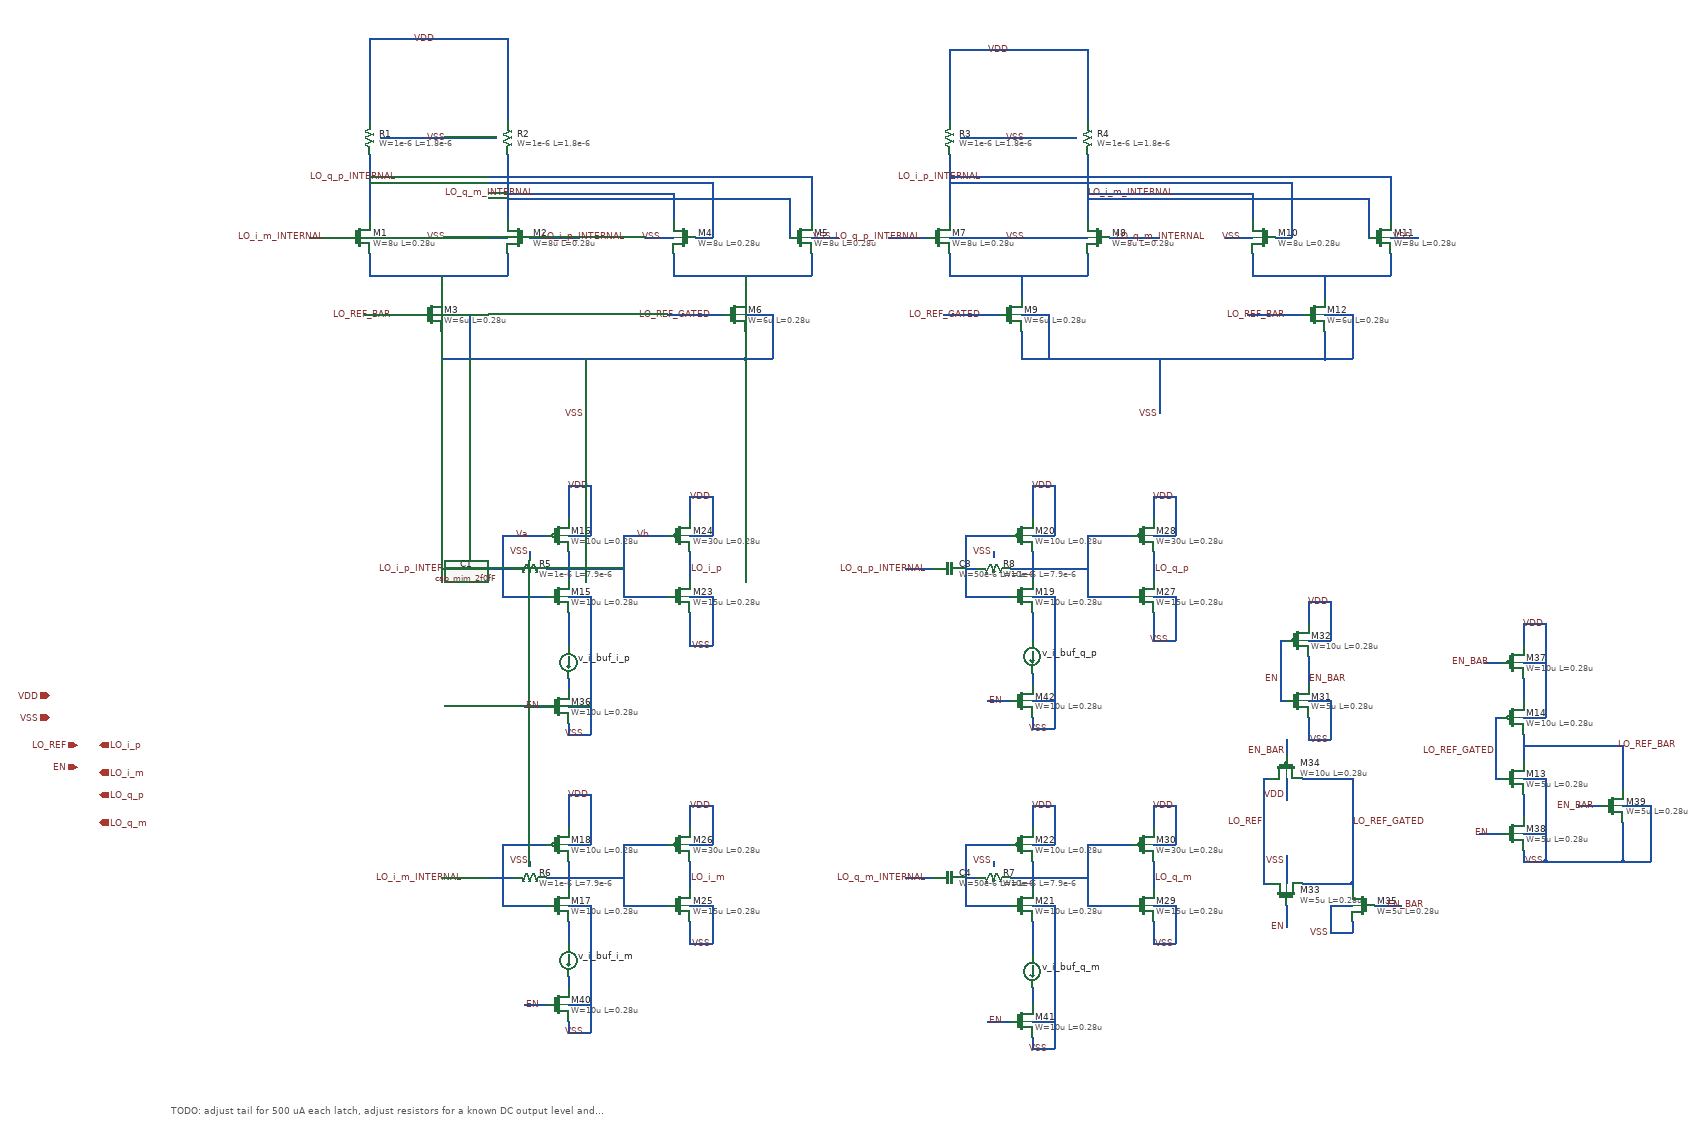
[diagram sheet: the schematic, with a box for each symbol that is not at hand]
v {xschem version=3.4.8RC file_version=1.3}
G {}
K {}
V {}
S {}
F {}
E {}
T {TODO: adjust tail for 500 uA each latch, adjust resistors for a known DC output level and swing, add latch output stage to couple into output buffer. Remove self biasing or add wideband buffer to help with low frequency clock signasl} 50 170 0 0 0.2 0.2 {}
N 410 -1370 410 -1330 {lab=#net1}
N 410 -1330 660 -1330 {lab=#net1}
N 660 -1370 660 -1330 {lab=#net1}
N 540 -1330 540 -1290 {lab=#net1}
N 400 -1260 500 -1260 {lab=LO_REF_BAR}
N 540 -1230 540 -1180 {lab=VSS}
N 300 -1400 370 -1400 {lab=LO_i_m_INTERNAL}
N 700 -1400 790 -1400 {lab=LO_i_p_INTERNAL}
N 660 -1540 660 -1430 {lab=LO_q_m_INTERNAL}
N 410 -1550 410 -1430 {lab=LO_q_p_INTERNAL}
N 410 -1760 660 -1760 {lab=VDD}
N 960 -1370 960 -1330 {lab=#net2}
N 960 -1330 1210 -1330 {lab=#net2}
N 1210 -1370 1210 -1330 {lab=#net2}
N 1090 -1330 1090 -1290 {lab=#net2}
N 950 -1260 1050 -1260 {lab=LO_REF_GATED}
N 1090 -1230 1090 -1180 {lab=VSS}
N 960 -1480 960 -1430 {lab=LO_q_m_INTERNAL}
N 1000 -1400 1030 -1400 {lab=LO_q_p_INTERNAL}
N 1030 -1450 1030 -1400 {lab=LO_q_p_INTERNAL}
N 660 -1480 960 -1480 {lab=LO_q_m_INTERNAL}
N 1030 -1500 1030 -1450 {lab=LO_q_p_INTERNAL}
N 410 -1500 1030 -1500 {lab=LO_q_p_INTERNAL}
N 1170 -1470 1170 -1400 {lab=LO_q_m_INTERNAL}
N 660 -1470 1170 -1470 {lab=LO_q_m_INTERNAL}
N 1210 -1510 1210 -1430 {lab=LO_q_p_INTERNAL}
N 410 -1510 1210 -1510 {lab=LO_q_p_INTERNAL}
N 540 -1180 1090 -1180 {lab=VSS}
N 540 -1260 590 -1260 {lab=VSS}
N 590 -1250 590 -1180 {lab=VSS}
N 590 -1260 590 -1250 {lab=VSS}
N 1090 -1260 1140 -1260 {lab=VSS}
N 1140 -1260 1140 -1180 {lab=VSS}
N 1090 -1180 1140 -1180 {lab=VSS}
N 910 -1400 960 -1400 {lab=VSS}
N 1210 -1400 1260 -1400 {lab=VSS}
N 410 -1400 660 -1400 {lab=VSS}
N 1460 -1370 1460 -1330 {lab=#net3}
N 1460 -1330 1710 -1330 {lab=#net3}
N 1710 -1370 1710 -1330 {lab=#net3}
N 1590 -1330 1590 -1290 {lab=#net3}
N 1450 -1260 1550 -1260 {lab=LO_REF_GATED}
N 1590 -1230 1590 -1180 {lab=VSS}
N 1350 -1400 1420 -1400 {lab=LO_q_p_INTERNAL}
N 1750 -1400 1840 -1400 {lab=LO_q_m_INTERNAL}
N 1710 -1540 1710 -1430 {lab=LO_i_m_INTERNAL}
N 1460 -1550 1460 -1430 {lab=LO_i_p_INTERNAL}
N 1460 -1740 1710 -1740 {lab=VDD}
N 2010 -1370 2010 -1330 {lab=#net4}
N 2010 -1330 2260 -1330 {lab=#net4}
N 2260 -1370 2260 -1330 {lab=#net4}
N 2140 -1330 2140 -1290 {lab=#net4}
N 2000 -1260 2100 -1260 {lab=LO_REF_BAR}
N 2140 -1230 2140 -1180 {lab=VSS}
N 2010 -1480 2010 -1430 {lab=LO_i_m_INTERNAL}
N 2050 -1400 2080 -1400 {lab=LO_i_p_INTERNAL}
N 2080 -1450 2080 -1400 {lab=LO_i_p_INTERNAL}
N 1710 -1480 2010 -1480 {lab=LO_i_m_INTERNAL}
N 2080 -1500 2080 -1450 {lab=LO_i_p_INTERNAL}
N 1460 -1500 2080 -1500 {lab=LO_i_p_INTERNAL}
N 2220 -1470 2220 -1400 {lab=LO_i_m_INTERNAL}
N 1710 -1470 2220 -1470 {lab=LO_i_m_INTERNAL}
N 2260 -1510 2260 -1430 {lab=LO_i_p_INTERNAL}
N 1460 -1510 2260 -1510 {lab=LO_i_p_INTERNAL}
N 1590 -1180 2140 -1180 {lab=VSS}
N 1590 -1260 1640 -1260 {lab=VSS}
N 1640 -1250 1640 -1180 {lab=VSS}
N 1640 -1260 1640 -1250 {lab=VSS}
N 2140 -1260 2190 -1260 {lab=VSS}
N 2190 -1260 2190 -1180 {lab=VSS}
N 2140 -1180 2190 -1180 {lab=VSS}
N 1960 -1400 2010 -1400 {lab=VSS}
N 2260 -1400 2310 -1400 {lab=VSS}
N 1460 -1400 1710 -1400 {lab=VSS}
N 1840 -1120 1840 -1080 {lab=VSS}
N 800 -1120 800 -1080 {lab=VSS}
N 2450 -420 2460 -420 {lab=LO_REF_GATED}
N 2450 -530 2450 -420 {lab=LO_REF_GATED}
N 2450 -530 2460 -530 {lab=LO_REF_GATED}
N 2500 -500 2500 -450 {lab=LO_REF_BAR}
N 2500 -390 2500 -350 {lab=#net5}
N 2500 -530 2540 -530 {lab=VDD}
N 2540 -700 2540 -530 {lab=VDD}
N 2500 -700 2540 -700 {lab=VDD}
N 2500 -420 2540 -420 {lab=VSS}
N 2540 -420 2540 -350 {lab=VSS}
N 2500 -270 2540 -270 {lab=VSS}
N 800 -1170 800 -1120 {lab=VSS}
N 800 -1180 800 -1170 {lab=VSS}
N 1840 -1180 1840 -1120 {lab=VSS}
N 410 -1700 410 -1650 {lab=VDD}
N 660 -1700 660 -1650 {lab=VDD}
N 720 -750 730 -750 {lab=LO_i_p_INTERNAL}
N 650 -860 650 -750 {lab=LO_i_p_INTERNAL}
N 720 -860 730 -860 {lab=LO_i_p_INTERNAL}
N 770 -830 770 -780 {lab=Vb}
N 770 -720 770 -680 {lab=#net6}
N 770 -930 770 -890 {lab=VDD}
N 770 -860 810 -860 {lab=VDD}
N 770 -950 810 -950 {lab=VDD}
N 770 -750 810 -750 {lab=VSS}
N 810 -750 810 -680 {lab=VSS}
N 650 -750 720 -750 {lab=LO_i_p_INTERNAL}
N 650 -860 710 -860 {lab=LO_i_p_INTERNAL}
N 710 -860 720 -860 {lab=LO_i_p_INTERNAL}
N 730 -800 770 -800 {lab=Vb}
N 650 -800 670 -800 {lab=LO_i_p_INTERNAL}
N 540 -800 590 -800 {lab=LO_i_p_INTERNAL}
N 720 -190 730 -190 {lab=LO_i_m_INTERNAL}
N 650 -300 650 -190 {lab=LO_i_m_INTERNAL}
N 720 -300 730 -300 {lab=LO_i_m_INTERNAL}
N 770 -270 770 -220 {lab=#net7}
N 770 -370 770 -330 {lab=VDD}
N 770 -300 810 -300 {lab=VDD}
N 770 -190 810 -190 {lab=VSS}
N 650 -190 720 -190 {lab=LO_i_m_INTERNAL}
N 650 -300 710 -300 {lab=LO_i_m_INTERNAL}
N 710 -300 720 -300 {lab=LO_i_m_INTERNAL}
N 730 -240 770 -240 {lab=#net7}
N 650 -240 670 -240 {lab=LO_i_m_INTERNAL}
N 540 -240 590 -240 {lab=LO_i_m_INTERNAL}
N 1560 -750 1570 -750 {lab=#net8}
N 1490 -860 1490 -750 {lab=#net8}
N 1560 -860 1570 -860 {lab=#net8}
N 1610 -830 1610 -780 {lab=#net9}
N 1610 -720 1610 -680 {lab=#net10}
N 1610 -930 1610 -890 {lab=VDD}
N 1610 -860 1650 -860 {lab=VDD}
N 1610 -750 1650 -750 {lab=VSS}
N 1490 -750 1560 -750 {lab=#net8}
N 1490 -860 1550 -860 {lab=#net8}
N 1550 -860 1560 -860 {lab=#net8}
N 1570 -800 1610 -800 {lab=#net9}
N 1490 -800 1510 -800 {lab=#net8}
N 1380 -800 1430 -800 {lab=LO_q_p_INTERNAL}
N 1560 -190 1570 -190 {lab=#net11}
N 1490 -300 1490 -190 {lab=#net11}
N 1560 -300 1570 -300 {lab=#net11}
N 1610 -270 1610 -220 {lab=#net12}
N 1610 -370 1610 -330 {lab=VDD}
N 1610 -300 1650 -300 {lab=VDD}
N 1610 -190 1650 -190 {lab=VSS}
N 1490 -190 1560 -190 {lab=#net11}
N 1490 -300 1550 -300 {lab=#net11}
N 1550 -300 1560 -300 {lab=#net11}
N 1570 -240 1610 -240 {lab=#net12}
N 1490 -240 1510 -240 {lab=#net11}
N 1380 -240 1430 -240 {lab=LO_q_m_INTERNAL}
N 940 -750 950 -750 {lab=Vb}
N 940 -860 950 -860 {lab=Vb}
N 990 -830 990 -780 {lab=LO_i_p}
N 990 -720 990 -680 {lab=VSS}
N 990 -930 990 -890 {lab=VDD}
N 990 -860 1030 -860 {lab=VDD}
N 1030 -930 1030 -860 {lab=VDD}
N 990 -930 1030 -930 {lab=VDD}
N 990 -750 1030 -750 {lab=VSS}
N 870 -750 940 -750 {lab=Vb}
N 870 -860 930 -860 {lab=Vb}
N 930 -860 940 -860 {lab=Vb}
N 870 -860 870 -750 {lab=Vb}
N 770 -800 870 -800 {lab=Vb}
N 940 -190 950 -190 {lab=#net7}
N 940 -300 950 -300 {lab=#net7}
N 990 -270 990 -220 {lab=LO_i_m}
N 990 -370 990 -330 {lab=VDD}
N 990 -300 1030 -300 {lab=VDD}
N 1030 -370 1030 -300 {lab=VDD}
N 990 -370 1030 -370 {lab=VDD}
N 990 -190 1030 -190 {lab=VSS}
N 870 -190 940 -190 {lab=#net7}
N 870 -300 930 -300 {lab=#net7}
N 930 -300 940 -300 {lab=#net7}
N 870 -300 870 -190 {lab=#net7}
N 770 -240 870 -240 {lab=#net7}
N 1780 -750 1790 -750 {lab=#net9}
N 1780 -860 1790 -860 {lab=#net9}
N 1830 -830 1830 -780 {lab=LO_q_p}
N 1830 -720 1830 -680 {lab=VSS}
N 1830 -930 1830 -890 {lab=VDD}
N 1830 -860 1870 -860 {lab=VDD}
N 1870 -930 1870 -860 {lab=VDD}
N 1830 -930 1870 -930 {lab=VDD}
N 1830 -750 1870 -750 {lab=VSS}
N 1710 -750 1780 -750 {lab=#net9}
N 1710 -860 1770 -860 {lab=#net9}
N 1770 -860 1780 -860 {lab=#net9}
N 1710 -860 1710 -750 {lab=#net9}
N 1610 -800 1710 -800 {lab=#net9}
N 1780 -190 1790 -190 {lab=#net12}
N 1780 -300 1790 -300 {lab=#net12}
N 1830 -270 1830 -220 {lab=LO_q_m}
N 1830 -370 1830 -330 {lab=VDD}
N 1830 -300 1870 -300 {lab=VDD}
N 1870 -370 1870 -300 {lab=VDD}
N 1830 -370 1870 -370 {lab=VDD}
N 1830 -190 1870 -190 {lab=VSS
}
N 1710 -190 1780 -190 {lab=#net12}
N 1710 -300 1770 -300 {lab=#net12}
N 1770 -300 1780 -300 {lab=#net12}
N 1710 -300 1710 -190 {lab=#net12}
N 1610 -240 1710 -240 {lab=#net12}
N 2060 -560 2070 -560 {lab=EN}
N 2060 -670 2060 -560 {lab=EN}
N 2060 -670 2070 -670 {lab=EN}
N 2110 -640 2110 -590 {lab=EN_BAR}
N 2110 -530 2110 -490 {lab=VSS}
N 2110 -740 2110 -700 {lab=VDD}
N 2110 -670 2150 -670 {lab=VDD}
N 2150 -740 2150 -670 {lab=VDD}
N 2110 -740 2150 -740 {lab=VDD}
N 2110 -560 2150 -560 {lab=VSS}
N 2150 -560 2150 -490 {lab=VSS}
N 2110 -490 2150 -490 {lab=VSS}
N 2030 -230 2040 -230 {lab=LO_REF}
N 2030 -420 2030 -230 {lab=LO_REF}
N 2030 -420 2040 -420 {lab=LO_REF}
N 2100 -230 2190 -230 {lab=LO_REF_GATED}
N 2070 -420 2070 -380 {lab=VDD}
N 2070 -280 2070 -230 {lab=VSS}
N 2070 -190 2070 -150 {lab=EN}
N 2070 -490 2070 -460 {lab=EN_BAR}
N 2190 -230 2190 -220 {lab=LO_REF_GATED}
N 2230 -190 2280 -190 {lab=EN_BAR}
N 2150 -190 2190 -190 {lab=VSS}
N 2150 -190 2150 -140 {lab=VSS}
N 2150 -140 2190 -140 {lab=VSS}
N 2190 -160 2190 -140 {lab=VSS}
N 2500 -600 2500 -560 {lab=#net13}
N 2500 -630 2540 -630 {lab=VDD}
N 2500 -700 2500 -660 {lab=VDD}
N 2430 -630 2460 -630 {lab=EN_BAR}
N 2540 -350 2540 -270 {lab=VSS}
N 2500 -290 2500 -270 {lab=VSS}
N 2420 -320 2460 -320 {lab=EN}
N 2500 -480 2670 -480 {lab=LO_REF_BAR}
N 2670 -480 2680 -480 {lab=LO_REF_BAR}
N 2680 -480 2680 -400 {lab=LO_REF_BAR}
N 2680 -340 2680 -270 {lab=VSS}
N 2540 -270 2680 -270 {lab=VSS}
N 2680 -370 2730 -370 {lab=VSS}
N 2730 -370 2730 -270 {lab=VSS}
N 2680 -270 2730 -270 {lab=VSS}
N 2600 -370 2640 -370 {lab=EN_BAR}
N 2100 -420 2190 -420 {lab=LO_REF_GATED}
N 2190 -420 2190 -230 {lab=LO_REF_GATED}
N 770 -680 770 -660 {lab=#net6}
N 1030 -750 1030 -680 {lab=VSS}
N 1030 -190 1030 -140 {lab=VSS}
N 810 -190 810 -140 {lab=VSS}
N 1460 -1680 1460 -1610 {lab=VDD}
N 2500 -320 2540 -320 {lab=VSS}
N 1650 -100 1650 -50 {lab=VSS}
N 1870 -190 1870 -140 {lab=VSS}
N 1650 -740 1650 -700 {lab=VSS}
N 1650 -750 1650 -740 {lab=VSS}
N 1870 -750 1870 -700 {lab=VSS}
N 410 -1650 410 -1610 {lab=VDD}
N 660 -1550 660 -1540 {lab=LO_q_m_INTERNAL}
N 660 -1650 660 -1610 {lab=VDD}
N 430 -1580 640 -1580 {lab=VSS}
N 1480 -1580 1690 -1580 {lab=VSS}
N 1710 -1550 1710 -1540 {lab=LO_i_m_INTERNAL}
N 1710 -1680 1710 -1610 {lab=VDD}
N 700 -830 700 -820 {lab=VSS}
N 700 -270 700 -260 {lab=VSS}
N 1540 -270 1540 -260 {lab=VSS}
N 1540 -830 1540 -820 {lab=VSS}
N 410 -1760 410 -1700 {lab=VDD}
N 660 -1760 660 -1700 {lab=VDD}
N 1460 -1740 1460 -1680 {lab=VDD}
N 1710 -1740 1710 -1680 {lab=VDD}
N 810 -680 810 -660 {lab=VSS}
N 770 -500 810 -500 {lab=VSS}
N 1030 -680 1030 -660 {lab=VSS}
N 990 -660 1030 -660 {lab=VSS}
N 990 -680 990 -660 {lab=VSS}
N 770 -160 770 -130 {lab=#net14}
N 770 -130 770 -120 {lab=#net14}
N 810 -140 810 -120 {lab=VSS}
N 990 -160 990 -130 {lab=VSS}
N 990 -130 990 -120 {lab=VSS}
N 990 -120 1030 -120 {lab=VSS}
N 1030 -140 1030 -120 {lab=VSS}
N 1610 -680 1610 -670 {lab=#net10}
N 1650 -700 1650 -670 {lab=VSS}
N 1830 -680 1830 -670 {lab=VSS}
N 1830 -670 1870 -670 {lab=VSS}
N 1870 -700 1870 -670 {lab=VSS}
N 1610 -160 1610 -120 {lab=#net15}
N 1650 -40 1650 -30 {lab=VSS}
N 1650 -50 1650 -40 {lab=VSS}
N 1830 -160 1830 -120 {lab=VSS}
N 1830 -120 1870 -120 {lab=VSS}
N 1870 -140 1870 -120 {lab=VSS}
N 770 -950 770 -930 {lab=VDD}
N 1610 -950 1650 -950 {lab=VDD}
N 1610 -950 1610 -930 {lab=VDD}
N 770 -390 810 -390 {lab=VDD}
N 770 -390 770 -370 {lab=VDD}
N 1610 -370 1650 -370 {lab=VDD}
N 1610 -40 1610 -30 {lab=#net16}
N 1610 -120 1610 -100 {lab=#net15}
N 1650 -190 1650 -100 {lab=VSS}
N 1650 -370 1650 -300 {lab=VDD}
N 1650 -670 1650 -610 {lab=VSS}
N 1650 -950 1650 -860 {lab=VDD}
N 810 -660 810 -600 {lab=VSS}
N 810 -950 810 -860 {lab=VDD}
N 810 -120 810 -60 {lab=VSS}
N 810 -390 810 -300 {lab=VDD}
N 770 -520 770 -500 {lab=VSS}
N 770 -550 810 -550 {lab=VSS}
N 810 -600 810 -500 {lab=VSS}
N 770 -600 770 -580 {lab=#net17}
N 690 -550 730 -550 {lab=EN}
N 770 40 810 40 {lab=VSS}
N 770 20 770 40 {lab=VSS}
N 770 -10 810 -10 {lab=VSS}
N 810 -60 810 40 {lab=VSS}
N 770 -60 770 -40 {lab=#net18}
N 690 -10 730 -10 {lab=EN}
N 1610 70 1650 70 {lab=VSS}
N 1610 50 1610 70 {lab=VSS}
N 1610 20 1650 20 {lab=VSS}
N 1650 -30 1650 70 {lab=VSS}
N 1610 -30 1610 -10 {lab=#net16}
N 1530 20 1570 20 {lab=EN}
N 1610 -510 1650 -510 {lab=VSS}
N 1610 -530 1610 -510 {lab=VSS}
N 1610 -560 1650 -560 {lab=VSS}
N 1650 -610 1650 -510 {lab=VSS}
N 1610 -610 1610 -590 {lab=#net19}
N 1530 -560 1570 -560 {lab=EN}
N 590 -800 650 -800 {lab=LO_i_p_INTERNAL}
N 590 -240 650 -240 {lab=LO_i_m_INTERNAL}
C {title.sym} 160 110 0 0 {name=LO Divider author="Lei Chen"}
C {symbols/nfet_03v3.sym} 390 -1400 0 0 {name=M1
L=0.28u
W=8u
nf=1
m=1
ad="'int((nf+1)/2) * W/nf * 0.18u'"
pd="'2*int((nf+1)/2) * (W/nf + 0.18u)'"
as="'int((nf+2)/2) * W/nf * 0.18u'"
ps="'2*int((nf+2)/2) * (W/nf + 0.18u)'"
nrd="'0.18u / W'" nrs="'0.18u / W'"
sa=0 sb=0 sd=0
model=nfet_03v3
spiceprefix=X
}
C {symbols/nfet_03v3.sym} 680 -1400 0 1 {name=M2
L=0.28u
W=8u
nf=1
m=1
ad="'int((nf+1)/2) * W/nf * 0.18u'"
pd="'2*int((nf+1)/2) * (W/nf + 0.18u)'"
as="'int((nf+2)/2) * W/nf * 0.18u'"
ps="'2*int((nf+2)/2) * (W/nf + 0.18u)'"
nrd="'0.18u / W'" nrs="'0.18u / W'"
sa=0 sb=0 sd=0
model=nfet_03v3
spiceprefix=X
}
C {symbols/nfet_03v3.sym} 520 -1260 0 0 {name=M3
L=0.28u
W=6u
nf=1
m=1
ad="'int((nf+1)/2) * W/nf * 0.18u'"
pd="'2*int((nf+1)/2) * (W/nf + 0.18u)'"
as="'int((nf+2)/2) * W/nf * 0.18u'"
ps="'2*int((nf+2)/2) * (W/nf + 0.18u)'"
nrd="'0.18u / W'" nrs="'0.18u / W'"
sa=0 sb=0 sd=0
model=nfet_03v3
spiceprefix=X
}
C {symbols/nfet_03v3.sym} 980 -1400 0 1 {name=M4
L=0.28u
W=8u
nf=1
m=1
ad="'int((nf+1)/2) * W/nf * 0.18u'"
pd="'2*int((nf+1)/2) * (W/nf + 0.18u)'"
as="'int((nf+2)/2) * W/nf * 0.18u'"
ps="'2*int((nf+2)/2) * (W/nf + 0.18u)'"
nrd="'0.18u / W'" nrs="'0.18u / W'"
sa=0 sb=0 sd=0
model=nfet_03v3
spiceprefix=X
}
C {symbols/nfet_03v3.sym} 1190 -1400 0 0 {name=M5
L=0.28u
W=8u
nf=1
m=1
ad="'int((nf+1)/2) * W/nf * 0.18u'"
pd="'2*int((nf+1)/2) * (W/nf + 0.18u)'"
as="'int((nf+2)/2) * W/nf * 0.18u'"
ps="'2*int((nf+2)/2) * (W/nf + 0.18u)'"
nrd="'0.18u / W'" nrs="'0.18u / W'"
sa=0 sb=0 sd=0
model=nfet_03v3
spiceprefix=X
}
C {symbols/nfet_03v3.sym} 1070 -1260 0 0 {name=M6
L=0.28u
W=6u
nf=1
m=1
ad="'int((nf+1)/2) * W/nf * 0.18u'"
pd="'2*int((nf+1)/2) * (W/nf + 0.18u)'"
as="'int((nf+2)/2) * W/nf * 0.18u'"
ps="'2*int((nf+2)/2) * (W/nf + 0.18u)'"
nrd="'0.18u / W'" nrs="'0.18u / W'"
sa=0 sb=0 sd=0
model=nfet_03v3
spiceprefix=X
}
C {iopin.sym} -170 -570 0 0 {name=p1 lab=VDD}
C {iopin.sym} -170 -530 0 0 {name=p2 lab=VSS}
C {ipin.sym} -120 -480 0 0 {name=p3 lab=LO_REF}
C {opin.sym} -80 -480 0 0 {name=p5 lab=LO_i_p}
C {opin.sym} -80 -430 0 0 {name=p6 lab=LO_i_m}
C {lab_wire.sym} 800 -1080 0 0 {name=p7 sig_type=std_logic lab=VSS}
C {lab_wire.sym} 450 -1260 0 0 {name=p8 sig_type=std_logic lab=LO_REF_BAR}
C {lab_wire.sym} 550 -1400 0 0 {name=p12 sig_type=std_logic lab=VSS}
C {lab_wire.sym} 530 -1760 0 0 {name=p15 sig_type=std_logic lab=VDD}
C {lab_wire.sym} 940 -1400 0 0 {name=p16 sig_type=std_logic lab=VSS}
C {lab_wire.sym} 1250 -1400 0 0 {name=p17 sig_type=std_logic lab=VSS}
C {symbols/nfet_03v3.sym} 1440 -1400 0 0 {name=M7
L=0.28u
W=8u
nf=1
m=1
ad="'int((nf+1)/2) * W/nf * 0.18u'"
pd="'2*int((nf+1)/2) * (W/nf + 0.18u)'"
as="'int((nf+2)/2) * W/nf * 0.18u'"
ps="'2*int((nf+2)/2) * (W/nf + 0.18u)'"
nrd="'0.18u / W'" nrs="'0.18u / W'"
sa=0 sb=0 sd=0
model=nfet_03v3
spiceprefix=X
}
C {symbols/nfet_03v3.sym} 1730 -1400 0 1 {name=M8
L=0.28u
W=8u
nf=1
m=1
ad="'int((nf+1)/2) * W/nf * 0.18u'"
pd="'2*int((nf+1)/2) * (W/nf + 0.18u)'"
as="'int((nf+2)/2) * W/nf * 0.18u'"
ps="'2*int((nf+2)/2) * (W/nf + 0.18u)'"
nrd="'0.18u / W'" nrs="'0.18u / W'"
sa=0 sb=0 sd=0
model=nfet_03v3
spiceprefix=X
}
C {symbols/nfet_03v3.sym} 1570 -1260 0 0 {name=M9
L=0.28u
W=6u
nf=1
m=1
ad="'int((nf+1)/2) * W/nf * 0.18u'"
pd="'2*int((nf+1)/2) * (W/nf + 0.18u)'"
as="'int((nf+2)/2) * W/nf * 0.18u'"
ps="'2*int((nf+2)/2) * (W/nf + 0.18u)'"
nrd="'0.18u / W'" nrs="'0.18u / W'"
sa=0 sb=0 sd=0
model=nfet_03v3
spiceprefix=X
}
C {symbols/nfet_03v3.sym} 2030 -1400 0 1 {name=M10
L=0.28u
W=8u
nf=1
m=1
ad="'int((nf+1)/2) * W/nf * 0.18u'"
pd="'2*int((nf+1)/2) * (W/nf + 0.18u)'"
as="'int((nf+2)/2) * W/nf * 0.18u'"
ps="'2*int((nf+2)/2) * (W/nf + 0.18u)'"
nrd="'0.18u / W'" nrs="'0.18u / W'"
sa=0 sb=0 sd=0
model=nfet_03v3
spiceprefix=X
}
C {symbols/nfet_03v3.sym} 2240 -1400 0 0 {name=M11
L=0.28u
W=8u
nf=1
m=1
ad="'int((nf+1)/2) * W/nf * 0.18u'"
pd="'2*int((nf+1)/2) * (W/nf + 0.18u)'"
as="'int((nf+2)/2) * W/nf * 0.18u'"
ps="'2*int((nf+2)/2) * (W/nf + 0.18u)'"
nrd="'0.18u / W'" nrs="'0.18u / W'"
sa=0 sb=0 sd=0
model=nfet_03v3
spiceprefix=X
}
C {symbols/nfet_03v3.sym} 2120 -1260 0 0 {name=M12
L=0.28u
W=6u
nf=1
m=1
ad="'int((nf+1)/2) * W/nf * 0.18u'"
pd="'2*int((nf+1)/2) * (W/nf + 0.18u)'"
as="'int((nf+2)/2) * W/nf * 0.18u'"
ps="'2*int((nf+2)/2) * (W/nf + 0.18u)'"
nrd="'0.18u / W'" nrs="'0.18u / W'"
sa=0 sb=0 sd=0
model=nfet_03v3
spiceprefix=X
}
C {lab_wire.sym} 1840 -1080 0 0 {name=p18 sig_type=std_logic lab=VSS}
C {lab_wire.sym} 2070 -1260 0 0 {name=p20 sig_type=std_logic lab=LO_REF_BAR}
C {lab_wire.sym} 1600 -1400 0 0 {name=p23 sig_type=std_logic lab=VSS}
C {lab_wire.sym} 1570 -1740 0 0 {name=p26 sig_type=std_logic lab=VDD}
C {lab_wire.sym} 1990 -1400 0 0 {name=p27 sig_type=std_logic lab=VSS}
C {lab_wire.sym} 2300 -1400 0 0 {name=p28 sig_type=std_logic lab=VSS}
C {opin.sym} -80 -390 0 0 {name=p29 lab=LO_q_p}
C {opin.sym} -80 -340 0 0 {name=p30 lab=LO_q_m}
C {symbols/nfet_03v3.sym} 2480 -420 0 0 {name=M13
L=0.28u
W=5u
nf=1
m=1
ad="'int((nf+1)/2) * W/nf * 0.18u'"
pd="'2*int((nf+1)/2) * (W/nf + 0.18u)'"
as="'int((nf+2)/2) * W/nf * 0.18u'"
ps="'2*int((nf+2)/2) * (W/nf + 0.18u)'"
nrd="'0.18u / W'" nrs="'0.18u / W'"
sa=0 sb=0 sd=0
model=nfet_03v3
spiceprefix=X
}
C {symbols/pfet_03v3.sym} 2480 -530 0 0 {name=M14
L=0.28u
W=10u
nf=1
m=1
ad="'int((nf+1)/2) * W/nf * 0.18u'"
pd="'2*int((nf+1)/2) * (W/nf + 0.18u)'"
as="'int((nf+2)/2) * W/nf * 0.18u'"
ps="'2*int((nf+2)/2) * (W/nf + 0.18u)'"
nrd="'0.18u / W'" nrs="'0.18u / W'"
sa=0 sb=0 sd=0
model=pfet_03v3
spiceprefix=X
}
C {lab_wire.sym} 2540 -700 0 0 {name=p4 sig_type=std_logic lab=VDD}
C {lab_wire.sym} 2540 -270 0 0 {name=p31 sig_type=std_logic lab=VSS}
C {lab_wire.sym} 2030 -340 0 0 {name=p32 sig_type=std_logic lab=LO_REF}
C {lab_wire.sym} 2670 -480 0 1 {name=p33 sig_type=std_logic lab=LO_REF_BAR}
C {symbols/nfet_03v3.sym} 750 -750 0 0 {name=M15
L=0.28u
W=10u
nf=1
m=1
ad="'int((nf+1)/2) * W/nf * 0.18u'"
pd="'2*int((nf+1)/2) * (W/nf + 0.18u)'"
as="'int((nf+2)/2) * W/nf * 0.18u'"
ps="'2*int((nf+2)/2) * (W/nf + 0.18u)'"
nrd="'0.18u / W'" nrs="'0.18u / W'"
sa=0 sb=0 sd=0
model=nfet_03v3
spiceprefix=X
}
C {symbols/pfet_03v3.sym} 750 -860 0 0 {name=M16
L=0.28u
W=10u
nf=1
m=1
ad="'int((nf+1)/2) * W/nf * 0.18u'"
pd="'2*int((nf+1)/2) * (W/nf + 0.18u)'"
as="'int((nf+2)/2) * W/nf * 0.18u'"
ps="'2*int((nf+2)/2) * (W/nf + 0.18u)'"
nrd="'0.18u / W'" nrs="'0.18u / W'"
sa=0 sb=0 sd=0
model=pfet_03v3
spiceprefix=X
}
C {lab_wire.sym} 810 -950 0 0 {name=p34 sig_type=std_logic lab=VDD}
C {lab_wire.sym} 580 -800 0 0 {name=p36 sig_type=std_logic lab=LO_i_p_INTERNAL}
C {symbols/nfet_03v3.sym} 750 -190 0 0 {name=M17
L=0.28u
W=10u
nf=1
m=1
ad="'int((nf+1)/2) * W/nf * 0.18u'"
pd="'2*int((nf+1)/2) * (W/nf + 0.18u)'"
as="'int((nf+2)/2) * W/nf * 0.18u'"
ps="'2*int((nf+2)/2) * (W/nf + 0.18u)'"
nrd="'0.18u / W'" nrs="'0.18u / W'"
sa=0 sb=0 sd=0
model=nfet_03v3
spiceprefix=X
}
C {symbols/pfet_03v3.sym} 750 -300 0 0 {name=M18
L=0.28u
W=10u
nf=1
m=1
ad="'int((nf+1)/2) * W/nf * 0.18u'"
pd="'2*int((nf+1)/2) * (W/nf + 0.18u)'"
as="'int((nf+2)/2) * W/nf * 0.18u'"
ps="'2*int((nf+2)/2) * (W/nf + 0.18u)'"
nrd="'0.18u / W'" nrs="'0.18u / W'"
sa=0 sb=0 sd=0
model=pfet_03v3
spiceprefix=X
}
C {lab_wire.sym} 580 -240 0 0 {name=p39 sig_type=std_logic lab=LO_i_m_INTERNAL}
C {symbols/nfet_03v3.sym} 1590 -750 0 0 {name=M19
L=0.28u
W=10u
nf=1
m=1
ad="'int((nf+1)/2) * W/nf * 0.18u'"
pd="'2*int((nf+1)/2) * (W/nf + 0.18u)'"
as="'int((nf+2)/2) * W/nf * 0.18u'"
ps="'2*int((nf+2)/2) * (W/nf + 0.18u)'"
nrd="'0.18u / W'" nrs="'0.18u / W'"
sa=0 sb=0 sd=0
model=nfet_03v3
spiceprefix=X
}
C {symbols/pfet_03v3.sym} 1590 -860 0 0 {name=M20
L=0.28u
W=10u
nf=1
m=1
ad="'int((nf+1)/2) * W/nf * 0.18u'"
pd="'2*int((nf+1)/2) * (W/nf + 0.18u)'"
as="'int((nf+2)/2) * W/nf * 0.18u'"
ps="'2*int((nf+2)/2) * (W/nf + 0.18u)'"
nrd="'0.18u / W'" nrs="'0.18u / W'"
sa=0 sb=0 sd=0
model=pfet_03v3
spiceprefix=X
}
C {lab_wire.sym} 1420 -800 0 0 {name=p44 sig_type=std_logic lab=LO_q_p_INTERNAL}
C {symbols/nfet_03v3.sym} 1590 -190 0 0 {name=M21
L=0.28u
W=10u
nf=1
m=1
ad="'int((nf+1)/2) * W/nf * 0.18u'"
pd="'2*int((nf+1)/2) * (W/nf + 0.18u)'"
as="'int((nf+2)/2) * W/nf * 0.18u'"
ps="'2*int((nf+2)/2) * (W/nf + 0.18u)'"
nrd="'0.18u / W'" nrs="'0.18u / W'"
sa=0 sb=0 sd=0
model=nfet_03v3
spiceprefix=X
}
C {symbols/pfet_03v3.sym} 1590 -300 0 0 {name=M22
L=0.28u
W=10u
nf=1
m=1
ad="'int((nf+1)/2) * W/nf * 0.18u'"
pd="'2*int((nf+1)/2) * (W/nf + 0.18u)'"
as="'int((nf+2)/2) * W/nf * 0.18u'"
ps="'2*int((nf+2)/2) * (W/nf + 0.18u)'"
nrd="'0.18u / W'" nrs="'0.18u / W'"
sa=0 sb=0 sd=0
model=pfet_03v3
spiceprefix=X
}
C {lab_wire.sym} 1420 -240 0 0 {name=p47 sig_type=std_logic lab=LO_q_m_INTERNAL}
C {symbols/pfet_03v3.sym} 970 -860 0 0 {name=M24
L=0.28u
W=30u
nf=1
m=1
ad="'int((nf+1)/2) * W/nf * 0.18u'"
pd="'2*int((nf+1)/2) * (W/nf + 0.18u)'"
as="'int((nf+2)/2) * W/nf * 0.18u'"
ps="'2*int((nf+2)/2) * (W/nf + 0.18u)'"
nrd="'0.18u / W'" nrs="'0.18u / W'"
sa=0 sb=0 sd=0
model=pfet_03v3
spiceprefix=X
}
C {lab_wire.sym} 1030 -930 0 0 {name=p40 sig_type=std_logic lab=VDD}
C {lab_wire.sym} 990 -800 0 1 {name=p48 sig_type=std_logic lab=LO_i_p}
C {symbols/pfet_03v3.sym} 970 -300 0 0 {name=M26
L=0.28u
W=30u
nf=1
m=1
ad="'int((nf+1)/2) * W/nf * 0.18u'"
pd="'2*int((nf+1)/2) * (W/nf + 0.18u)'"
as="'int((nf+2)/2) * W/nf * 0.18u'"
ps="'2*int((nf+2)/2) * (W/nf + 0.18u)'"
nrd="'0.18u / W'" nrs="'0.18u / W'"
sa=0 sb=0 sd=0
model=pfet_03v3
spiceprefix=X
}
C {lab_wire.sym} 1030 -370 0 0 {name=p49 sig_type=std_logic lab=VDD}
C {lab_wire.sym} 990 -240 0 1 {name=p51 sig_type=std_logic lab=LO_i_m}
C {symbols/pfet_03v3.sym} 1810 -860 0 0 {name=M28
L=0.28u
W=30u
nf=1
m=1
ad="'int((nf+1)/2) * W/nf * 0.18u'"
pd="'2*int((nf+1)/2) * (W/nf + 0.18u)'"
as="'int((nf+2)/2) * W/nf * 0.18u'"
ps="'2*int((nf+2)/2) * (W/nf + 0.18u)'"
nrd="'0.18u / W'" nrs="'0.18u / W'"
sa=0 sb=0 sd=0
model=pfet_03v3
spiceprefix=X
}
C {lab_wire.sym} 1870 -930 0 0 {name=p52 sig_type=std_logic lab=VDD}
C {lab_wire.sym} 1830 -800 0 1 {name=p54 sig_type=std_logic lab=LO_q_p}
C {symbols/pfet_03v3.sym} 1810 -300 0 0 {name=M30
L=0.28u
W=30u
nf=1
m=1
ad="'int((nf+1)/2) * W/nf * 0.18u'"
pd="'2*int((nf+1)/2) * (W/nf + 0.18u)'"
as="'int((nf+2)/2) * W/nf * 0.18u'"
ps="'2*int((nf+2)/2) * (W/nf + 0.18u)'"
nrd="'0.18u / W'" nrs="'0.18u / W'"
sa=0 sb=0 sd=0
model=pfet_03v3
spiceprefix=X
}
C {lab_wire.sym} 1870 -370 0 0 {name=p55 sig_type=std_logic lab=VDD}
C {lab_wire.sym} 1830 -240 0 1 {name=p56 sig_type=std_logic lab=LO_q_m}
C {ipin.sym} -120 -440 0 0 {name=p58 lab=EN}
C {symbols/nfet_03v3.sym} 2090 -560 0 0 {name=M31
L=0.28u
W=5u
nf=1
m=1
ad="'int((nf+1)/2) * W/nf * 0.18u'"
pd="'2*int((nf+1)/2) * (W/nf + 0.18u)'"
as="'int((nf+2)/2) * W/nf * 0.18u'"
ps="'2*int((nf+2)/2) * (W/nf + 0.18u)'"
nrd="'0.18u / W'" nrs="'0.18u / W'"
sa=0 sb=0 sd=0
model=nfet_03v3
spiceprefix=X
}
C {symbols/pfet_03v3.sym} 2090 -670 0 0 {name=M32
L=0.28u
W=10u
nf=1
m=1
ad="'int((nf+1)/2) * W/nf * 0.18u'"
pd="'2*int((nf+1)/2) * (W/nf + 0.18u)'"
as="'int((nf+2)/2) * W/nf * 0.18u'"
ps="'2*int((nf+2)/2) * (W/nf + 0.18u)'"
nrd="'0.18u / W'" nrs="'0.18u / W'"
sa=0 sb=0 sd=0
model=pfet_03v3
spiceprefix=X
}
C {lab_wire.sym} 2150 -740 0 0 {name=p59 sig_type=std_logic lab=VDD}
C {lab_wire.sym} 2150 -490 0 0 {name=p60 sig_type=std_logic lab=VSS}
C {lab_wire.sym} 2060 -600 0 0 {name=p61 sig_type=std_logic lab=EN}
C {lab_wire.sym} 2110 -600 0 1 {name=p62 sig_type=std_logic lab=EN_BAR}
C {symbols/nfet_03v3.sym} 2070 -210 3 0 {name=M33
L=0.28u
W=5u
nf=1
m=1
ad="'int((nf+1)/2) * W/nf * 0.18u'"
pd="'2*int((nf+1)/2) * (W/nf + 0.18u)'"
as="'int((nf+2)/2) * W/nf * 0.18u'"
ps="'2*int((nf+2)/2) * (W/nf + 0.18u)'"
nrd="'0.18u / W'" nrs="'0.18u / W'"
sa=0 sb=0 sd=0
model=nfet_03v3
spiceprefix=X
}
C {symbols/pfet_03v3.sym} 2070 -440 3 1 {name=M34
L=0.28u
W=10u
nf=1
m=1
ad="'int((nf+1)/2) * W/nf * 0.18u'"
pd="'2*int((nf+1)/2) * (W/nf + 0.18u)'"
as="'int((nf+2)/2) * W/nf * 0.18u'"
ps="'2*int((nf+2)/2) * (W/nf + 0.18u)'"
nrd="'0.18u / W'" nrs="'0.18u / W'"
sa=0 sb=0 sd=0
model=pfet_03v3
spiceprefix=X
}
C {lab_wire.sym} 2190 -340 0 1 {name=p63 sig_type=std_logic lab=LO_REF_GATED}
C {lab_wire.sym} 1520 -1260 0 0 {name=p9 sig_type=std_logic lab=LO_REF_GATED}
C {lab_wire.sym} 1030 -1260 0 0 {name=p19 sig_type=std_logic lab=LO_REF_GATED}
C {lab_wire.sym} 2070 -270 0 0 {name=p65 sig_type=std_logic lab=VSS}
C {lab_wire.sym} 2070 -390 0 0 {name=p66 sig_type=std_logic lab=VDD}
C {lab_wire.sym} 2070 -150 0 0 {name=p68 sig_type=std_logic lab=EN}
C {lab_wire.sym} 2070 -470 0 0 {name=p69 sig_type=std_logic lab=EN_BAR}
C {symbols/nfet_03v3.sym} 2210 -190 0 1 {name=M35
L=0.28u
W=5u
nf=1
m=1
ad="'int((nf+1)/2) * W/nf * 0.18u'"
pd="'2*int((nf+1)/2) * (W/nf + 0.18u)'"
as="'int((nf+2)/2) * W/nf * 0.18u'"
ps="'2*int((nf+2)/2) * (W/nf + 0.18u)'"
nrd="'0.18u / W'" nrs="'0.18u / W'"
sa=0 sb=0 sd=0
model=nfet_03v3
spiceprefix=X
}
C {lab_wire.sym} 2150 -140 0 0 {name=p67 sig_type=std_logic lab=VSS}
C {lab_wire.sym} 2250 -190 0 1 {name=p70 sig_type=std_logic lab=EN_BAR}
C {symbols/pfet_03v3.sym} 2480 -630 0 0 {name=M37
L=0.28u
W=10u
nf=1
m=1
ad="'int((nf+1)/2) * W/nf * 0.18u'"
pd="'2*int((nf+1)/2) * (W/nf + 0.18u)'"
as="'int((nf+2)/2) * W/nf * 0.18u'"
ps="'2*int((nf+2)/2) * (W/nf + 0.18u)'"
nrd="'0.18u / W'" nrs="'0.18u / W'"
sa=0 sb=0 sd=0
model=pfet_03v3
spiceprefix=X
}
C {lab_wire.sym} 2440 -630 0 0 {name=p64 sig_type=std_logic lab=EN_BAR}
C {symbols/nfet_03v3.sym} 2480 -320 0 0 {name=M38
L=0.28u
W=5u
nf=1
m=1
ad="'int((nf+1)/2) * W/nf * 0.18u'"
pd="'2*int((nf+1)/2) * (W/nf + 0.18u)'"
as="'int((nf+2)/2) * W/nf * 0.18u'"
ps="'2*int((nf+2)/2) * (W/nf + 0.18u)'"
nrd="'0.18u / W'" nrs="'0.18u / W'"
sa=0 sb=0 sd=0
model=nfet_03v3
spiceprefix=X
}
C {lab_wire.sym} 2450 -470 0 0 {name=p74 sig_type=std_logic lab=LO_REF_GATED}
C {lab_wire.sym} 2440 -320 0 0 {name=p73 sig_type=std_logic lab=EN}
C {symbols/nfet_03v3.sym} 2660 -370 0 0 {name=M39
L=0.28u
W=5u
nf=1
m=1
ad="'int((nf+1)/2) * W/nf * 0.18u'"
pd="'2*int((nf+1)/2) * (W/nf + 0.18u)'"
as="'int((nf+2)/2) * W/nf * 0.18u'"
ps="'2*int((nf+2)/2) * (W/nf + 0.18u)'"
nrd="'0.18u / W'" nrs="'0.18u / W'"
sa=0 sb=0 sd=0
model=nfet_03v3
spiceprefix=X
}
C {lab_wire.sym} 2630 -370 0 0 {name=p75 sig_type=std_logic lab=EN_BAR}
C {symbols/ppolyf_u_1k.sym} 410 -1580 0 1 {name=R1
W=1e-6
L=1.8e-6
model=ppolyf_u_1k
spiceprefix=X
m=1}
C {symbols/ppolyf_u_1k.sym} 660 -1580 0 0 {name=R2
W=1e-6
L=1.8e-6
model=ppolyf_u_1k
spiceprefix=X
m=1}
C {lab_wire.sym} 550 -1580 0 0 {name=p82 sig_type=std_logic lab=VSS}
C {symbols/ppolyf_u_1k.sym} 1460 -1580 0 1 {name=R3
W=1e-6
L=1.8e-6
model=ppolyf_u_1k
spiceprefix=X
m=1}
C {symbols/ppolyf_u_1k.sym} 1710 -1580 0 0 {name=R4
W=1e-6
L=1.8e-6
model=ppolyf_u_1k
spiceprefix=X
m=1}
C {lab_wire.sym} 1600 -1580 0 0 {name=p83 sig_type=std_logic lab=VSS}
C {symbols/ppolyf_u_1k.sym} 700 -800 3 1 {name=R5
W=1e-6
L=7.9e-6
model=ppolyf_u_1k
spiceprefix=X
m=1
}
C {lab_wire.sym} 700 -830 0 0 {name=p84 sig_type=std_logic lab=VSS}
C {symbols/ppolyf_u_1k.sym} 700 -240 3 1 {name=R6
W=1e-6
L=7.9e-6
model=ppolyf_u_1k
spiceprefix=X
m=1}
C {lab_wire.sym} 700 -270 0 0 {name=p85 sig_type=std_logic lab=VSS}
C {symbols/ppolyf_u_1k.sym} 1540 -240 3 1 {name=R7
W=1e-6
L=7.9e-6
model=ppolyf_u_1k
spiceprefix=X
m=1}
C {lab_wire.sym} 1540 -270 0 0 {name=p86 sig_type=std_logic lab=VSS}
C {symbols/ppolyf_u_1k.sym} 1540 -800 3 1 {name=R8
W=1e-6
L=7.9e-6
model=ppolyf_u_1k
spiceprefix=X
m=1}
C {lab_wire.sym} 1540 -830 0 0 {name=p87 sig_type=std_logic lab=VSS}
C {symbols/cap_mim_2f0fF.sym} 610 -900 3 0 {name=C1
W=50e-6
L=10e-6
model=cap_mim_2f0fF
spiceprefix=X
m=1
spice_ignore=true}
C {symbols/cap_mim_2f0fF.sym} 1460 -800 3 0 {name=C3
W=50e-6
L=10e-6
model=cap_mim_2f0fF
spiceprefix=X
m=1}
C {symbols/cap_mim_2f0fF.sym} 1460 -240 3 0 {name=C4
W=50e-6
L=10e-6
model=cap_mim_2f0fF
spiceprefix=X
m=1}
C {lab_wire.sym} 330 -1400 0 0 {name=p10 sig_type=std_logic lab=LO_i_m_INTERNAL}
C {lab_wire.sym} 720 -1400 0 1 {name=p11 sig_type=std_logic lab=LO_i_p_INTERNAL}
C {lab_wire.sym} 460 -1510 0 0 {name=p13 sig_type=std_logic lab=LO_q_p_INTERNAL}
C {lab_wire.sym} 710 -1480 0 0 {name=p88 sig_type=std_logic lab=LO_q_m_INTERNAL}
C {lab_wire.sym} 1410 -1400 0 0 {name=p14 sig_type=std_logic lab=LO_q_p_INTERNAL}
C {lab_wire.sym} 1760 -1400 0 1 {name=p21 sig_type=std_logic lab=LO_q_m_INTERNAL}
C {lab_wire.sym} 1520 -1510 0 0 {name=p22 sig_type=std_logic lab=LO_i_p_INTERNAL}
C {lab_wire.sym} 1710 -1480 0 1 {name=p24 sig_type=std_logic lab=LO_i_m_INTERNAL}
C {lab_wire.sym} 800 -500 0 0 {name=p35 sig_type=std_logic lab=VSS}
C {lab_wire.sym} 1030 -660 0 0 {name=p38 sig_type=std_logic lab=VSS}
C {lab_wire.sym} 1030 -120 0 0 {name=p50 sig_type=std_logic lab=VSS}
C {lab_wire.sym} 1860 -670 0 0 {name=p46 sig_type=std_logic lab=VSS}
C {lab_wire.sym} 1870 -120 0 0 {name=p57 sig_type=std_logic lab=VSS}
C {symbols/nfet_03v3.sym} 970 -750 0 0 {name=M23
L=0.28u
W=15u
nf=1
m=1
ad="'int((nf+1)/2) * W/nf * 0.18u'"
pd="'2*int((nf+1)/2) * (W/nf + 0.18u)'"
as="'int((nf+2)/2) * W/nf * 0.18u'"
ps="'2*int((nf+2)/2) * (W/nf + 0.18u)'"
nrd="'0.18u / W'" nrs="'0.18u / W'"
sa=0 sb=0 sd=0
model=nfet_03v3
spiceprefix=X
}
C {symbols/nfet_03v3.sym} 970 -190 0 0 {name=M25
L=0.28u
W=15u
nf=1
m=1
ad="'int((nf+1)/2) * W/nf * 0.18u'"
pd="'2*int((nf+1)/2) * (W/nf + 0.18u)'"
as="'int((nf+2)/2) * W/nf * 0.18u'"
ps="'2*int((nf+2)/2) * (W/nf + 0.18u)'"
nrd="'0.18u / W'" nrs="'0.18u / W'"
sa=0 sb=0 sd=0
model=nfet_03v3
spiceprefix=X
}
C {symbols/nfet_03v3.sym} 1810 -750 0 0 {name=M27
L=0.28u
W=15u
nf=1
m=1
ad="'int((nf+1)/2) * W/nf * 0.18u'"
pd="'2*int((nf+1)/2) * (W/nf + 0.18u)'"
as="'int((nf+2)/2) * W/nf * 0.18u'"
ps="'2*int((nf+2)/2) * (W/nf + 0.18u)'"
nrd="'0.18u / W'" nrs="'0.18u / W'"
sa=0 sb=0 sd=0
model=nfet_03v3
spiceprefix=X
}
C {symbols/nfet_03v3.sym} 1810 -190 0 0 {name=M29
L=0.28u
W=15u
nf=1
m=1
ad="'int((nf+1)/2) * W/nf * 0.18u'"
pd="'2*int((nf+1)/2) * (W/nf + 0.18u)'"
as="'int((nf+2)/2) * W/nf * 0.18u'"
ps="'2*int((nf+2)/2) * (W/nf + 0.18u)'"
nrd="'0.18u / W'" nrs="'0.18u / W'"
sa=0 sb=0 sd=0
model=nfet_03v3
spiceprefix=X
}
C {ammeter.sym} 770 -630 0 0 {name=v_i_buf_i_p savecurrent=true spice_ignore=0}
C {lab_wire.sym} 1650 -950 0 0 {name=p92 sig_type=std_logic lab=VDD}
C {ammeter.sym} 1610 -640 0 0 {name=v_i_buf_q_p savecurrent=true spice_ignore=0}
C {lab_wire.sym} 810 -390 0 0 {name=p37 sig_type=std_logic lab=VDD}
C {ammeter.sym} 770 -90 0 0 {name=v_i_buf_i_m savecurrent=true spice_ignore=0}
C {lab_wire.sym} 1650 -370 0 0 {name=p42 sig_type=std_logic lab=VDD}
C {ammeter.sym} 1610 -70 0 0 {name=v_i_buf_q_m savecurrent=true spice_ignore=0}
C {symbols/nfet_03v3.sym} 750 -550 0 0 {name=M36
L=0.28u
W=10u
nf=1
m=1
ad="'int((nf+1)/2) * W/nf * 0.18u'"
pd="'2*int((nf+1)/2) * (W/nf + 0.18u)'"
as="'int((nf+2)/2) * W/nf * 0.18u'"
ps="'2*int((nf+2)/2) * (W/nf + 0.18u)'"
nrd="'0.18u / W'" nrs="'0.18u / W'"
sa=0 sb=0 sd=0
model=nfet_03v3
spiceprefix=X
}
C {lab_wire.sym} 720 -550 0 0 {name=p25 sig_type=std_logic lab=EN}
C {lab_wire.sym} 800 40 0 0 {name=p45 sig_type=std_logic lab=VSS}
C {symbols/nfet_03v3.sym} 750 -10 0 0 {name=M40
L=0.28u
W=10u
nf=1
m=1
ad="'int((nf+1)/2) * W/nf * 0.18u'"
pd="'2*int((nf+1)/2) * (W/nf + 0.18u)'"
as="'int((nf+2)/2) * W/nf * 0.18u'"
ps="'2*int((nf+2)/2) * (W/nf + 0.18u)'"
nrd="'0.18u / W'" nrs="'0.18u / W'"
sa=0 sb=0 sd=0
model=nfet_03v3
spiceprefix=X
}
C {lab_wire.sym} 720 -10 0 0 {name=p71 sig_type=std_logic lab=EN}
C {lab_wire.sym} 1640 70 0 0 {name=p41 sig_type=std_logic lab=VSS}
C {symbols/nfet_03v3.sym} 1590 20 0 0 {name=M41
L=0.28u
W=10u
nf=1
m=1
ad="'int((nf+1)/2) * W/nf * 0.18u'"
pd="'2*int((nf+1)/2) * (W/nf + 0.18u)'"
as="'int((nf+2)/2) * W/nf * 0.18u'"
ps="'2*int((nf+2)/2) * (W/nf + 0.18u)'"
nrd="'0.18u / W'" nrs="'0.18u / W'"
sa=0 sb=0 sd=0
model=nfet_03v3
spiceprefix=X
}
C {lab_wire.sym} 1560 20 0 0 {name=p72 sig_type=std_logic lab=EN}
C {lab_wire.sym} 1640 -510 0 0 {name=p53 sig_type=std_logic lab=VSS}
C {symbols/nfet_03v3.sym} 1590 -560 0 0 {name=M42
L=0.28u
W=10u
nf=1
m=1
ad="'int((nf+1)/2) * W/nf * 0.18u'"
pd="'2*int((nf+1)/2) * (W/nf + 0.18u)'"
as="'int((nf+2)/2) * W/nf * 0.18u'"
ps="'2*int((nf+2)/2) * (W/nf + 0.18u)'"
nrd="'0.18u / W'" nrs="'0.18u / W'"
sa=0 sb=0 sd=0
model=nfet_03v3
spiceprefix=X
}
C {lab_wire.sym} 1560 -560 0 0 {name=p76 sig_type=std_logic lab=EN}
C {lab_wire.sym} 700 -860 0 0 {name=p43 sig_type=std_logic lab=Va
spice_ignore=true}
C {lab_wire.sym} 920 -860 0 0 {name=p77 sig_type=std_logic lab=Vb}
